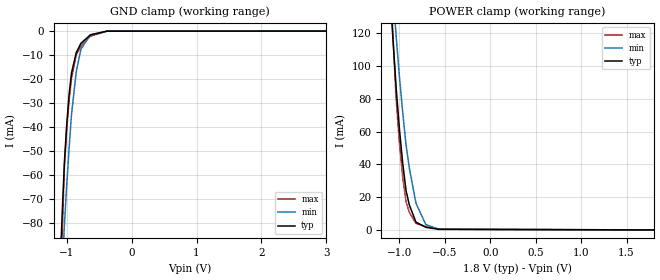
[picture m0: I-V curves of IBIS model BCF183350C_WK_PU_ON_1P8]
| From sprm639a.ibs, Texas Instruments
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|BCF183350C_WK_PD_ON_1P8; WEAK_PULLDOWN_ON
|   Model Cell BCF183350C_WK_PU_ON_1P8
|BCF183350C_WK_PU_ON_1P8
[Model]   BCF183350C_WK_PU_ON_1P8
Model_type   Input
Polarity   Non-Inverting
Vinl =  0.63
Vinh =  1.17
C_comp   1.111906p   0.9691991p   1.265789p
[Model Spec]
Vinl   0.63   0.63   0.63
Vinh   1.17   1.17   1.17
[Temperature Range]   25   155   -40
[Voltage Range]   1.8   1.62   1.98
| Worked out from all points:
|   GND clamp passes 1 mA (typ) near -0.60 V on its own axis
|   POWER clamp passes 1 mA (typ) near -0.65 V on its own axis
| Nom Voltages:
|   VDD=1.2, VDDS=1.8, VSS=0
| Min Voltages:
|   VDD=1.08, VDDS=1.62, VSS=0
| Max Voltages:
|   VDD=1.32, VDDS=1.98, VSS=0
[POWER_clamp]
|   voltage   I(typ)   I(min)   I(max)
-1.8V     884.3mA    853.3mA    1.248A
-1.109V   150.5mA    176mA      165.6mA
-1.073V   117.6mA    146.3mA    120.4mA
-1.036V   86.46mA    118mA      79.88mA
-1V       61.32mA    93.41mA    52.76mA
-963.6mV  40.46mA    71.37mA    31.87mA
-927.3mV  23.9mA     51.85mA    17.21mA
-890.9mV  15.18mA    37.69mA    10.66mA
-818.2mV  4.731mA    16.3mA     3.984mA
-709.1mV  1.569mA    3.203mA    2.036mA
-563.6mV  346uA      430.5uA    445.2uA
1.8V      -22.95uA   -10.4uA    -41.17uA
[GND_clamp]
|   voltage   I(typ)   I(min)   I(max)
-1.8V     -722.8mA   -541.3mA   -1.24A
-1.109V   -103.2mA   -119.1mA   -124.9mA
-1.073V   -77.59mA   -99.55mA   -86.64mA
-1.036V   -54.39mA   -80.71mA   -56.17mA
-1V       -38.52mA   -63.93mA   -40.94mA
-963.6mV  -26.23mA   -48.65mA   -28.77mA
-927.3mV  -17.51mA   -34.87mA   -19.65mA
-854.5mV  -9.047mA   -16.96mA   -9.997mA
-781.8mV  -5.081mA   -7.519mA   -6.26mA
-636.4mV  -1.594mA   -1.566mA   -2.137mA
-381.8mV  -30.33uA   -36.45uA   -47.86uA
3.6V      0A         0A         0A
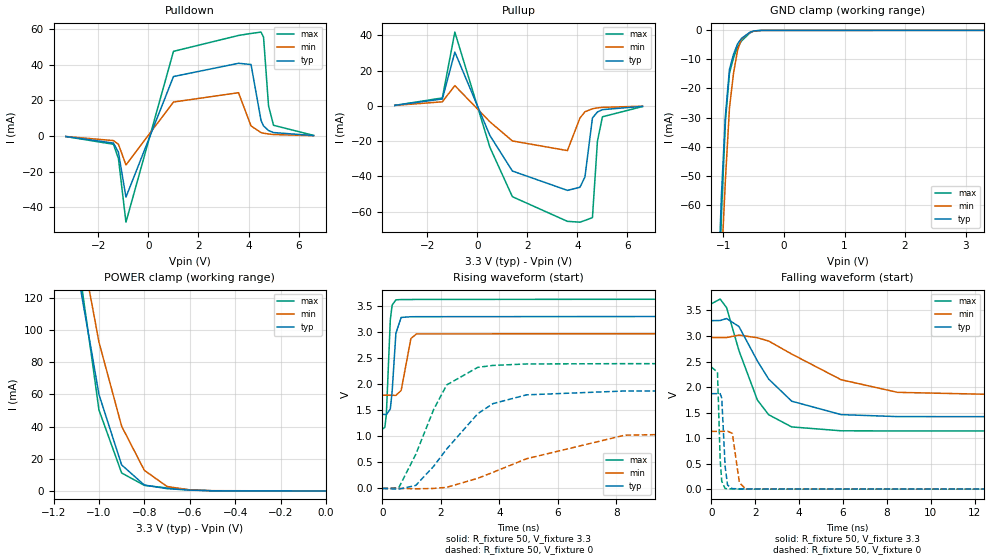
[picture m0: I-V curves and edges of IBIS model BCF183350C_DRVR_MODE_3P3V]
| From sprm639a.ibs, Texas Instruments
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|   Model Cell BCF183350C_DRVR_MODE_3P3V
|BCF183350C_DRVR_MODE_3P3V
[Model]   BCF183350C_DRVR_MODE_3P3V
Model_type   I/O
Polarity   Non-Inverting
Enable   Active-Low
Vinl =  0.8
Vinh =  2
Cref =  15.0000pF
Rref =  100.0000M
Vref =  0V
Vmeas =  1.65
C_comp   1.082155p   0.9471713p   1.221547p
[Model Spec]
Vinl   0.8   0.8   0.8
Vinh   2   2   2
[Temperature Range]   25   155   -40
[Voltage Range]   3.3   2.97   3.63
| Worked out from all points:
|   slope of the pulldown table from 0 to 0.495 V, typ, clamps not added: 24.2 ohm
|   slope of the pullup table from 0 to 0.495 V, typ, clamps not added: 29.8 ohm
|   GND clamp passes 1 mA (typ) near -0.59 V on its own axis
|   POWER clamp passes 1 mA (typ) near -0.65 V on its own axis
|   rising waveform, R_fixture 50, V_fixture 3.3: 20-80 % time 128ps typ, 198ps min, 102ps max; typ from 1.42 V to 3.3 V
|   rising waveform, R_fixture 50, V_fixture 0: 20-80 % time 1.71ns typ, 3.54ns min, 1.11ns max; typ from 0 V to 1.87 V
|   falling waveform, R_fixture 50, V_fixture 3.3: 20-80 % time 1.82ns typ, 3.49ns min, 1.28ns max; typ from 3.3 V to 1.42 V
|   falling waveform, R_fixture 50, V_fixture 0: 20-80 % time 116ps typ, 184ps min, 93.5ps max; typ from 1.87 V to 0 V
| Nom Voltages:
|   VDD=1.2, VDDS=3.3, VSS=0
| Min Voltages:
|   VDD=1.08, VDDS=2.97, VSS=0
| Max Voltages:
|   VDD=1.32, VDDS=3.63, VSS=0
[POWER_clamp]
|   voltage   I(typ)   I(min)   I(max)
-3.3V     2.318A     2.595A     3.049A
-1.1V     141.5mA    168mA      152.3mA
-1.067V   114.3mA    142.9mA    118.3mA
-1.033V   87.17mA    117.8mA    84.37mA
-1V       60.01mA    92.63mA    50.4mA
-900mV    16.17mA    40.25mA    11.16mA
-800mV    3.655mA    12.81mA    3.461mA
-700mV    1.415mA    2.754mA    1.844mA
-600mV    504.3uA    641.1uA    658.2uA
-500mV    86.55uA    148.2uA    94.22uA
0V        39.59pA    2.724nA    9.703pA
[Pulldown]
|   voltage   I(typ)   I(min)   I(max)
-3.3V     -252.1uA   -234.7uA   -277.7uA
-1.4V     -3.919mA   -2.547mA   -4.608mA
-1.2V     -9.103mA   -4.609mA   -12.64mA
-900mV    -34.3mA    -16.21mA   -48.36mA
1V        33.43mA    19.12mA    47.58mA
3.6V      40.87mA    24.35mA    56.5mA
4.1V      40.18mA    5.681mA    57.63mA
4.5V      8.744mA    1.956mA    58.39mA
4.6V      5.703mA    1.616mA    55.56mA
4.8V      3.099mA    1.152mA    16.91mA
5V        1.969mA    859.8uA    6.049mA
6.6V      281.1uA    214.2uA    387.2uA
[Pullup]
|   voltage   I(typ)   I(min)   I(max)
-3.3V     278.9uA    242.8uA    252.3uA
-1.4V     3.885mA    2.29mA     4.485mA
-900mV    30.46mA    11.45mA    41.76mA
500mV     -16.76mA   -9.024mA   -23.45mA
1.4V      -36.9mA    -19.86mA   -51.44mA
3.6V      -47.86mA   -25.33mA   -65.39mA
4.1V      -46.11mA   -6.928mA   -65.87mA
4.3V      -40.29mA   -3.368mA   -64.88mA
4.6V      -6.878mA   -1.656mA   -63.29mA
4.8V      -3.477mA   -1.154mA   -20.01mA
5V        -2.143mA   -846.4uA   -6.19mA
6.6V      -290.9uA   -205.6uA   -395.4uA
[GND_clamp]
|   voltage   I(typ)   I(min)   I(max)
-3.3V     -1.888A    -1.585A    -3.154A
-1.1V     -95.78mA   -113.9mA   -112.1mA
-1.033V   -56.7mA    -80.3mA    -63.61mA
-966.7mV  -29.24mA   -51.23mA   -31.16mA
-900mV    -13.41mA   -26.67mA   -14.73mA
-833.3mV  -8.233mA   -14.78mA   -9.457mA
-766.7mV  -4.676mA   -6.859mA   -5.761mA
-700mV    -2.737mA   -2.908mA   -3.644mA
-566.7mV  -742.7uA   -781uA     -966.3uA
-500mV    -188.9uA   -280.3uA   -215.5uA
-366.7mV  -8.774uA   -27.7uA    -8.181uA
3.3V      39.6pA     4.205uA    5.431pA
[Ramp]
| variable   typ   min   max
dV/dt_f  1.1758617/1.846144n  0.73903365/3.5514619n  1.5506713/1.2961218n
dV/dt_r  1.1445796/1.7390229n 0.69388235/3.5983554n  1.4637814/1.1275634n
R_load = 50
[Rising Waveform]
R_fixture = 50
V_fixture = 3.3
V_fixture_min = 2.97
V_fixture_max = 3.63
|   time   V(typ)   V(min)   V(max)
0s        1.419V     1.788V     1.139V
82.8ps    1.418V     1.788V     1.17V
135.4ps   1.416V     1.788V     1.423V
269.5ps   1.522V     1.788V     3.228V
331.9ps   1.853V     1.787V     3.513V
460.8ps   2.974V     1.783V     3.615V
641.7ps   3.278V     1.879V     3.621V
973.8ps   3.291V     2.874V     3.621V
1.165ns   3.292V     2.962V     3.623V
20.01ns   3.3V       2.97V      3.63V
[Rising Waveform]
R_fixture = 50
V_fixture = 0
V_fixture_min = 0
V_fixture_max = 0
|   time   V(typ)   V(min)   V(max)
0s        0V         0V         0V
559.4ps   -13.78mV   0V         13.79mV
1.138ns   57.09mV    -6.903mV   650.1mV
1.753ns   424.7mV    0V         1.513V
2.2ns     757.2mV    21.76mV    1.985V
3.262ns   1.433V     194.6mV    2.321V
3.783ns   1.626V     309.6mV    2.358V
4.93ns    1.794V     569.5mV    2.386V
8.289ns   1.868V     1.021V     2.392V
20.06ns   1.87V      1.132V     2.392V
[Falling Waveform]
R_fixture = 50
V_fixture = 3.3
V_fixture_min = 2.97
V_fixture_max = 3.63
|   time   V(typ)   V(min)   V(max)
0s        3.3V       2.97V      3.63V
402ps     3.303V     2.97V      3.723V
697.8ps   3.342V     2.97V      3.554V
1.261ns   3.184V     3.018V     2.711V
2.099ns   2.511V     2.965V     1.746V
2.613ns   2.156V     2.901V     1.458V
3.663ns   1.723V     2.646V     1.219V
5.917ns   1.46V      2.143V     1.143V
8.488ns   1.421V     1.896V     1.14V
20.01ns   1.419V     1.788V     1.14V
[Falling Waveform]
R_fixture = 50
V_fixture = 0
V_fixture_min = 0
V_fixture_max = 0
|   time   V(typ)   V(min)   V(max)
0s        1.87V      1.132V     2.392V
281.2ps   1.871V     1.132V     2.29V
404ps     1.87V      1.132V     574.1mV
475.6ps   1.785V     1.132V     154.5mV
629.2ps   444.4mV    1.133V     13.38mV
738.5ps   81.72mV    1.136V     6.36mV
959.5ps   10.14mV    1.091V     6.086mV
1.28ns    6.86mV     128.8mV    2.471mV
1.552ns   5.081mV    7.456mV    0V
20.06ns   0V         0V         0V
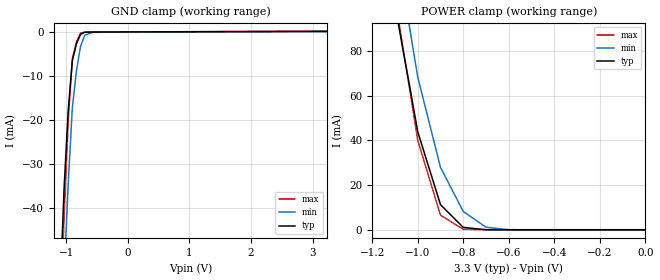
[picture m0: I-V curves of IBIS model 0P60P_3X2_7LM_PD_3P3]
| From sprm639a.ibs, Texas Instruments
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|   Model Cell 0P60P_3X2_7LM_PD_3P3
|IQ0442FS_40P60P_3X2_PD_3P3
[Model]   0P60P_3X2_7LM_PD_3P3
Model_type   Input
Polarity   Non-Inverting
Vinl =  1.55
Vinh =  1.75
C_comp   1.2p   1.2p   1.2p
[Model Spec]
Vinl   1.55   1.42   1.68
Vinh   1.75   1.55   1.85
[Temperature Range]   25   155   -40
[Voltage Range]   3.3   2.97   3.63
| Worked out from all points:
|   GND clamp passes 1 mA (typ) near -0.78 V on its own axis
|   POWER clamp passes 1 mA (typ) near -0.78 V on its own axis
[POWER_clamp]
|   voltage   I(typ)   I(min)   I(max)
-3.3V     1.823A     2.351A     1.96A
-1.1V     100.7mA    129.7mA    104mA
-1.067V   81.79mA    109.2mA    82.71mA
-1.033V   62.86mA    88.78mA    61.4mA
-1V       43.93mA    68.32mA    40.09mA
-900mV    11.35mA    27.98mA    6.644mA
-800mV    1.193mA    8.315mA    343.1uA
-700mV    131.4uA    1.273mA    170.7uA
-600mV    97.55uA    154.6uA    168.7uA
0V        96.5uA     44.2uA     168.6uA
[GND_clamp]
|   voltage   I(typ)   I(min)   I(max)
-3.3V     -1.38A     -1.323A    -2.074A
-1.1V     -59.6mA    -79.12mA   -70.72mA
-1.033V   -35.49mA   -55.25mA   -41.83mA
-966.7mV  -17.83mA   -34.66mA   -20.31mA
-900mV    -6.6mA     -17.33mA   -6.147mA
-833.3mV  -2.744mA   -8.865mA   -2.295mA
-766.7mV  -575.7uA   -3.35mA    -279.2uA
-700mV    -96.31uA   -786.8uA   -98.86uA
-566.7mV  -52.15uA   -88.15uA   -76.87uA
3.233V    96.49uA    44.27uA    168.5uA
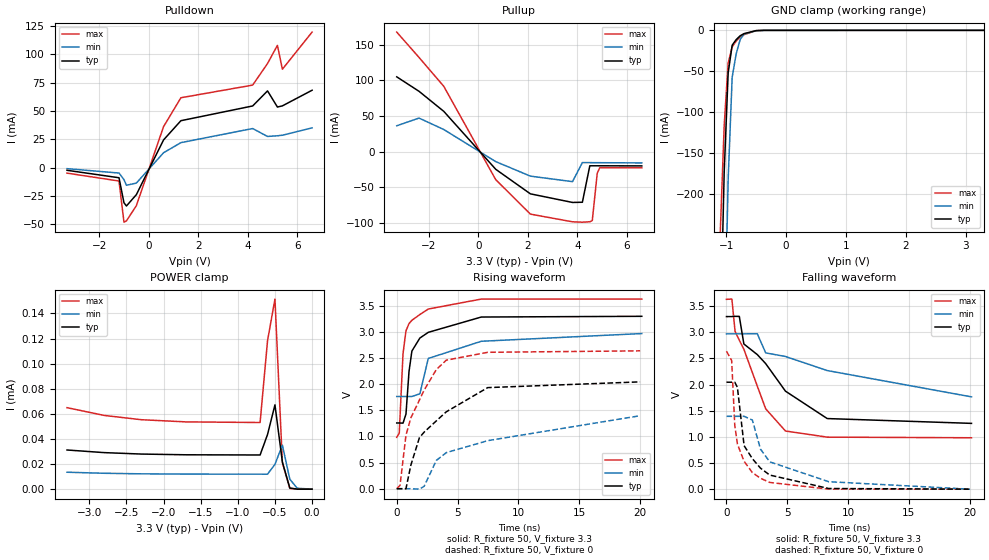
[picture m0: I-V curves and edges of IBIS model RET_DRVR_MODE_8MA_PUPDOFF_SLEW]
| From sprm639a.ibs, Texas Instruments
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|   Model Cell RET_DRVR_MODE_8MA_PUPDOFF_SLEW
|RET_DRVR_MODE_8MA_PUPDOFF_SLEW
[Model]   RET_DRVR_MODE_8MA_PUPDOFF_SLEW
Model_type   I/O
Polarity   Non-Inverting
Enable   Active-Low
Vinl =  0.8
Vinh =  2
Cref =  15.0000pF
Rref =  100.0000M
Vref =  0V
Vmeas =  1.65
C_comp   5.345208p   4.561426p   6.022817p
[Model Spec]
Vinl   0.8   0.8   0.8
Vinh   2   2   2
[Temperature Range]   25   155   -40
[Voltage Range]   3.3   2.97   3.63
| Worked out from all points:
|   slope of the pulldown table from 0 to 0.495 V, typ, clamps not added: 23.8 ohm
|   slope of the pullup table from 0 to 0.495 V, typ, clamps not added: 27.8 ohm
|   GND clamp passes 1 mA (typ) near -0.55 V on its own axis
|   rising waveform, R_fixture 50, V_fixture 3.3: 20-80 % time 1.11ns typ, 2.87ns min, 574ps max; typ from 1.26 V to 3.3 V
|   rising waveform, R_fixture 50, V_fixture 0: 20-80 % time 3.73ns typ, 8.01ns min, 2.27ns max; typ from 0 V to 2.04 V
|   falling waveform, R_fixture 50, V_fixture 3.3: 20-80 % time 4.3ns typ, 8.66ns min, 2.62ns max; typ from 3.3 V to 1.26 V
|   falling waveform, R_fixture 50, V_fixture 0: 20-80 % time 1.66ns typ, 3.52ns min, 947ps max; typ from 2.04 V to 0 V
| Nom Voltages:
|   BIASFET=3.3, VDD=1.2, VDDS=3.3, VSS=0
| Min Voltages:
|   BIASFET=2.97, VDD=1.08, VDDS=2.97, VSS=0
| Max Voltages:
|   BIASFET=3.63, VDD=1.32, VDDS=3.63, VSS=0
[POWER_clamp]
|   voltage   I(typ)   I(min)   I(max)
-3.3V     31.22uA    13.5uA     64.95uA
-2.8V     29.13uA    12.67uA    58.77uA
-2.3V     27.98uA    12.22uA    55.36uA
-1.7V     27.4uA     12.01uA    53.62uA
-700mV    27.24uA    11.95uA    53.12uA
-600mV    43.52uA    11.94uA    118.2uA
-500mV    67.2uA     19.79uA    151.5uA
-400mV    21.58uA    35.09uA    21.1uA
-300mV    927.4nA    7.958uA    611.4nA
-200mV    28.93nA    716.3nA    11.51nA
0V        696.9pA    39.48nA    568.3pA
[Pulldown]
|   voltage   I(typ)   I(min)   I(max)
-3.3V     -2.325mA   -885.1uA   -4.829mA
-1.2V     -8.9mA     -4.742mA   -11.78mA
-1V       -30.94mA   -10.56mA   -48.07mA
-900mV    -33.77mA   -15.53mA   -46.9mA
-500mV    -23.82mA   -13.61mA   -33.55mA
600mV     24.46mA    13.16mA    36.18mA
1.3V      41.39mA    22.04mA    61.62mA
4.2V      54.39mA    34.49mA    72.77mA
4.8V      67.66mA    27.49mA    91.8mA
5.2V      53.41mA    28.11mA    107.8mA
5.4V      54.46mA    28.58mA    86.79mA
6.6V      68.25mA    35.07mA    119.5mA
[Pullup]
|   voltage   I(typ)   I(min)   I(max)
-3.3V     105mA      36.43mA    167.7mA
-2.4V     84.74mA    47.23mA    132.2mA
-1.4V     56.66mA    31.22mA    91.73mA
700mV     -24.56mA   -13.78mA   -39.08mA
2.1V      -58.93mA   -34.12mA   -87.33mA
3.8V      -70.97mA   -41.82mA   -98.09mA
4.2V      -70.71mA   -15.14mA   -98.64mA
4.5V      -19.61mA   -15.2mA    -98.06mA
4.6V      -19.61mA   -15.22mA   -96.39mA
4.8V      -19.61mA   -15.26mA   -30.07mA
4.9V      -19.62mA   -15.28mA   -22.42mA
6.6V      -19.78mA   -15.6mA    -22.44mA
[GND_clamp]
|   voltage   I(typ)   I(min)   I(max)
-3.3V     -16.36A    -15.08A    -17.18A
-1.1V     -382.1mA   -717.8mA   -250.1mA
-1.033V   -173.3mA   -402.2mA   -116.4mA
-966.7mV  -52.02mA   -182.1mA   -39.81mA
-900mV    -18.21mA   -57.43mA   -20.34mA
-833.3mV  -11.36mA   -28.88mA   -13.17mA
-766.7mV  -6.618mA   -11.27mA   -8.134mA
-700mV    -3.983mA   -4.59mA    -5.247mA
-500mV    -328.3uA   -481.4uA   -374.5uA
-366.7mV  -15.94uA   -50.74uA   -14.83uA
3.3V      696.9pA    15.84uA    426.1pA
[Ramp]
| variable   typ   min   max
dV/dt_f  1.2310053/4.2984771n 0.72730904/8.6502749n  1.5950479/2.6227934n
dV/dt_r  1.2344632/3.7306612n 0.84436844/8.0035235n  1.5896397/2.2660664n
R_load = 50
[Rising Waveform]
R_fixture = 50
V_fixture = 3.3
V_fixture_min = 2.97
V_fixture_max = 3.63
|   time   V(typ)   V(min)   V(max)
0s        1.258V     1.765V     983.7mV
206.9ps   1.258V     1.765V     1.064V
516.9ps   1.255V     1.765V     2.584V
759.5ps   1.429V     1.765V     3.022V
1.01ns    2.244V     1.765V     3.161V
1.247ns   2.635V     1.765V     3.224V
1.901ns   2.884V     1.817V     3.334V
2.594ns   2.993V     2.493V     3.439V
6.952ns   3.286V     2.822V     3.63V
20.15ns   3.3V       2.97V      3.63V
[Rising Waveform]
R_fixture = 50
V_fixture = 0
V_fixture_min = 0
V_fixture_max = 0
|   time   V(typ)   V(min)   V(max)
0s        0V         0V         0V
270.4ps   0V         0V         65.09mV
758.6ps   0V         0V         1.024V
1.158ns   448.9mV    0V         1.354V
1.863ns   975.4mV    -8.845mV   1.696V
2.256ns   1.084V     46.58mV    1.888V
3.254ns   1.298V     540.6mV    2.28V
4.073ns   1.472V     690.5mV    2.46V
7.482ns   1.935V     919.8mV    2.611V
20.01ns   2.045V     1.397V     2.639V
[Falling Waveform]
R_fixture = 50
V_fixture = 3.3
V_fixture_min = 2.97
V_fixture_max = 3.63
|   time   V(typ)   V(min)   V(max)
0s        3.3V       2.97V      3.63V
446.6ps   3.3V       2.97V      3.635V
708.9ps   3.305V     2.97V      3.017V
1.059ns   3.303V     2.97V      2.846V
1.432ns   2.776V     2.97V      2.676V
2.538ns   2.573V     2.971V     1.97V
3.225ns   2.401V     2.606V     1.537V
4.853ns   1.874V     2.537V     1.112V
8.287ns   1.35V      2.268V     994.9mV
20.15ns   1.258V     1.765V     982.8mV
[Falling Waveform]
R_fixture = 50
V_fixture = 0
V_fixture_min = 0
V_fixture_max = 0
|   time   V(typ)   V(min)   V(max)
0s        2.045V     1.393V     2.639V
428.9ps   2.045V     1.393V     2.46V
683.5ps   2.046V     1.393V     1.227V
899.9ps   1.948V     1.393V     863.5mV
1.452ns   831.8mV    1.393V     532.3mV
2.131ns   583.4mV    1.322V     317.2mV
2.796ns   402.7mV    766.9mV    208.8mV
3.559ns   269.5mV    522.1mV    128.7mV
8.418ns   12.57mV    142.3mV    0V
20.01ns   0V         0V         0V
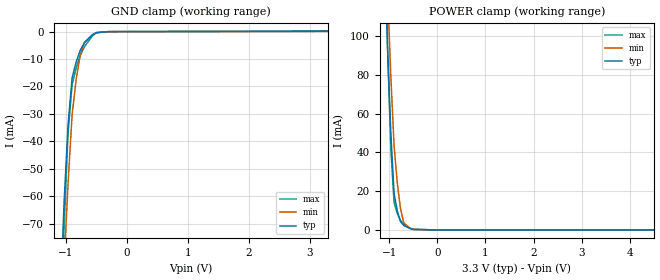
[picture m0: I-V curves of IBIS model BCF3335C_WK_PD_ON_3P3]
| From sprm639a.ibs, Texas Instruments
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|   Model Cell BCF3335C_WK_PD_ON_3P3
|BCF3335C_WK_PD_ON_3P3
[Model]   BCF3335C_WK_PD_ON_3P3
Model_type   Input
Polarity   Non-Inverting
Vinl =  0.8
Vinh =  2
C_comp   1.21278p   1.078036p   1.350148p
[Model Spec]
Vinl   0.8   0.8   0.8
Vinh   2   2   2
[Temperature Range]   25   155   -40
[Voltage Range]   3.3   2.97   3.63
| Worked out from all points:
|   GND clamp passes 1 mA (typ) near -0.55 V on its own axis
|   POWER clamp passes 1 mA (typ) near -0.59 V on its own axis
| Nom Voltages:
|   VDD=1.2, VDDS=3.3, VSS=0
| Min Voltages:
|   VDD=1.08, VDDS=2.97, VSS=0
| Max Voltages:
|   VDD=1.32, VDDS=3.63, VSS=0
[POWER_clamp]
|   voltage   I(typ)   I(min)   I(max)
-3.3V     2.319A     2.596A     3.052A
-1.1V     147.6mA    172.2mA    162.6mA
-1.033V   92.44mA    121.8mA    91.38mA
-966.7mV  49.54mA    78.89mA    41.94mA
-900mV    18.9mA     43.53mA    14.24mA
-833.3mV  9.848mA    24.4mA     8.546mA
-766.7mV  4.338mA    11.11mA    4.856mA
-700mV    2.371mA    3.663mA    3.173mA
-566.7mV  699.6uA    771.9uA    944.8uA
-500mV    248.7uA    286.4uA    332.8uA
33.33mV   0A         0A         0A
6.6V      0A         0A         0A
[GND_clamp]
|   voltage   I(typ)   I(min)   I(max)
-3.3V     -1.89A     -1.587A    -3.158A
-1.1V     -103.3mA   -119.1mA   -124.2mA
-1.033V   -62.96mA   -85.24mA   -71.87mA
-966.7mV  -34.19mA   -55.64mA   -36.89mA
-900mV    -16.94mA   -30.34mA   -19.31mA
-833.3mV  -11.09mA   -17.42mA   -13.31mA
-766.7mV  -6.833mA   -8.649mA   -8.755mA
-700mV    -4.167mA   -4.016mA   -5.634mA
-566.7mV  -1.181mA   -1.18mA    -1.555mA
-500mV    -336.1uA   -449.6uA   -399.2uA
-300mV    -27.98uA   -20.4uA    -40.75uA
3.3V      107.2uA    58.03uA    177.9uA
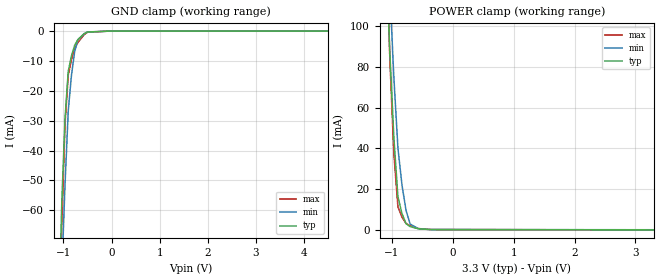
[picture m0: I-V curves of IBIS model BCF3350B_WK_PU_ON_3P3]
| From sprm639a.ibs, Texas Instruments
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|BCF3350B_WK_PD_ON_3P3; WEAK_PULLDOWN_ON
|   Model Cell BCF3350B_WK_PU_ON_3P3
|BCF3350B_WK_PU_ON_3P3
[Model]   BCF3350B_WK_PU_ON_3P3
Model_type   Input
Polarity   Non-Inverting
Vinl =  0.8
Vinh =  2
C_comp   1.081689p   0.9467568p   1.2214p
[Model Spec]
Vinl   0.8   0.8   0.8
Vinh   2   2   2
[Temperature Range]   25   155   -40
[Voltage Range]   3.3   2.97   3.63
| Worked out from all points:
|   GND clamp passes 1 mA (typ) near -0.58 V on its own axis
|   POWER clamp passes 1 mA (typ) near -0.65 V on its own axis
| Nom Voltages:
|   VDD=1.2, VDDS=3.3, VSS=0
| Min Voltages:
|   VDD=1.08, VDDS=2.97, VSS=0
| Max Voltages:
|   VDD=1.32, VDDS=3.63, VSS=0
[POWER_clamp]
|   voltage   I(typ)   I(min)   I(max)
-3.3V     2.318A     2.595A     3.049A
-1.1V     141.5mA    168mA      152.4mA
-1.033V   87.22mA    117.8mA    84.46mA
-966.7mV  45.45mA    75.19mA    37.43mA
-900mV    16.24mA    40.27mA    11.28mA
-833.3mV  7.9mA      21.98mA    6.136mA
-766.7mV  2.98mA     9.488mA    3.023mA
-700mV    1.481mA    2.786mA    1.936mA
-566.7mV  418.3uA    505.1uA    545.1uA
-366.7mV  37.54uA    32.82uA    50.64uA
3.3V      -108.8uA   -58.67uA   -174uA
[GND_clamp]
|   voltage   I(typ)   I(min)   I(max)
-3.3V     -1.888A    -1.585A    -3.154A
-1.1V     -95.8mA    -113.9mA   -112.1mA
-1.033V   -56.72mA   -80.31mA   -63.63mA
-966.7mV  -29.27mA   -51.24mA   -31.19mA
-900mV    -13.44mA   -26.69mA   -14.78mA
-833.3mV  -8.296mA   -14.8mA    -9.57mA
-766.7mV  -4.761mA   -6.885mA   -5.913mA
-700mV    -2.841mA   -2.943mA   -3.814mA
-566.7mV  -850.9uA   -829.9uA   -1.14mA
-500mV    -297.8uA   -331.1uA   -390.3uA
-33.33mV  0A         0A         0A
6.6V      0A         0A         0A
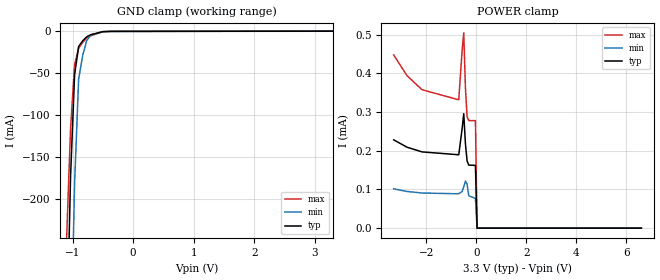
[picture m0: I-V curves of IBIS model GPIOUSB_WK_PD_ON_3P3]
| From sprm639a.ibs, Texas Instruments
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|USB_8MA_OPEN_DRAIN; 8MA_OPEN_DRAIN
|   Model Cell GPIOUSB_WK_PD_ON_3P3
|GPIOUSB_WK_PD_ON_3P3
[Model]   GPIOUSB_WK_PD_ON_3P3
Model_type   Input
Polarity   Non-Inverting
Vinl =  0.8
Vinh =  2
C_comp   5.34973p   4.565931p   6.027791p
[Model Spec]
Vinl   0.8   0.8   0.8
Vinh   2   2   2
[Temperature Range]   25   155   -40
[Voltage Range]   3.3   2.97   3.63
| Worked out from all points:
|   GND clamp passes 1 mA (typ) near -0.55 V on its own axis
| Nom Voltages:
|   BIASFET=3.3, VDD=1.2, VDDS=3.3, VSS=0
| Min Voltages:
|   BIASFET=2.97, VDD=1.08, VDDS=2.97, VSS=0
| Max Voltages:
|   BIASFET=3.63, VDD=1.32, VDDS=3.63, VSS=0
[POWER_clamp]
|   voltage   I(typ)   I(min)   I(max)
-3.3V     228.1uA    101.6uA    447.3uA
-2.767V   209.1uA    94.76uA    393.9uA
-2.167V   197uA      90.77uA    357.6uA
-700mV    189.6uA    88.78uA    331.6uA
-566.7mV  256.1uA    94.78uA    457.7uA
-500mV    295.8uA    106.8uA    504.4uA
-433.3mV  218.2uA    121.6uA    363.3uA
-366.7mV  173.9uA    113.9uA    287.8uA
-300mV    162.9uA    83.62uA    278.1uA
-33.33mV  162.2uA    76.8uA     277.6uA
33.33mV   0A         0A         0A
6.6V      0A         0A         0A
[GND_clamp]
|   voltage   I(typ)   I(min)   I(max)
-3.3V     -16.36A    -15.08A    -17.18A
-1.1V     -382.1mA   -717.8mA   -250.1mA
-1.033V   -173.3mA   -402.2mA   -116.4mA
-966.7mV  -52.02mA   -182.1mA   -39.8mA
-900mV    -18.2mA    -57.43mA   -20.33mA
-833.3mV  -11.36mA   -28.89mA   -13.17mA
-766.7mV  -6.626mA   -11.28mA   -8.158mA
-700mV    -4.013mA   -4.598mA   -5.306mA
-500mV    -405.1uA   -515.9uA   -494.1uA
-366.7mV  -78.5uA    -83.36uA   -110.5uA
3.3V      162.1uA    90.6uA     277.3uA
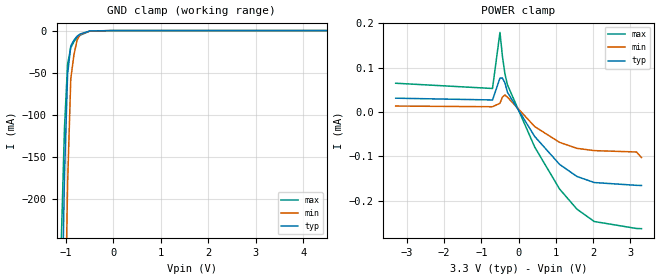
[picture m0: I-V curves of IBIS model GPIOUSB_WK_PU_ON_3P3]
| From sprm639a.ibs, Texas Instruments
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|   Model Cell GPIOUSB_WK_PU_ON_3P3
|GPIOUSB_WK_PU_ON_3P3
[Model]   GPIOUSB_WK_PU_ON_3P3
Model_type   Input
Polarity   Non-Inverting
Vinl =  0.8
Vinh =  2
C_comp   5.34973p   4.565931p   6.027791p
[Model Spec]
Vinl   0.8   0.8   0.8
Vinh   2   2   2
[Temperature Range]   25   155   -40
[Voltage Range]   3.3   2.97   3.63
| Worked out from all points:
|   GND clamp passes 1 mA (typ) near -0.54 V on its own axis
| Nom Voltages:
|   BIASFET=3.3, VDD=1.2, VDDS=3.3, VSS=0
| Min Voltages:
|   BIASFET=2.97, VDD=1.08, VDDS=2.97, VSS=0
| Max Voltages:
|   BIASFET=3.63, VDD=1.32, VDDS=3.63, VSS=0
[POWER_clamp]
|   voltage   I(typ)   I(min)   I(max)
-3.3V     31.22uA    13.5uA     64.95uA
-700mV    27.24uA    11.95uA    53.12uA
-500mV    76.48uA    19.77uA    179.6uA
-433.3mV  76.57uA    33.82uA    125.7uA
-366.7mV  66uA       38.46uA    86.4uA
-300mV    44.74uA    33.7uA     61.57uA
433.3mV   -55.14uA   -32.83uA   -78.95uA
1.1V      -118uA     -68.32uA   -173.5uA
1.567V    -145.3uA   -81.87uA   -219uA
2.033V    -159uA     -87.03uA   -246.9uA
3.167V    -165.3uA   -90.11uA   -262.6uA
3.3V      -165.6uA   -102.8uA   -263uA
[GND_clamp]
|   voltage   I(typ)   I(min)   I(max)
-3.3V     -16.36A    -15.08A    -17.18A
-1.1V     -382.1mA   -717.8mA   -250.1mA
-1.033V   -173.3mA   -402.2mA   -116.4mA
-966.7mV  -52.02mA   -182.1mA   -39.81mA
-900mV    -18.21mA   -57.44mA   -20.35mA
-833.3mV  -11.38mA   -28.89mA   -13.21mA
-766.7mV  -6.658mA   -11.29mA   -8.223mA
-700mV    -4.058mA   -4.616mA   -5.385mA
-500mV    -482.9uA   -556.9uA   -624.5uA
-33.33mV  0A         0A         0A
6.6V      0A         0A         0A
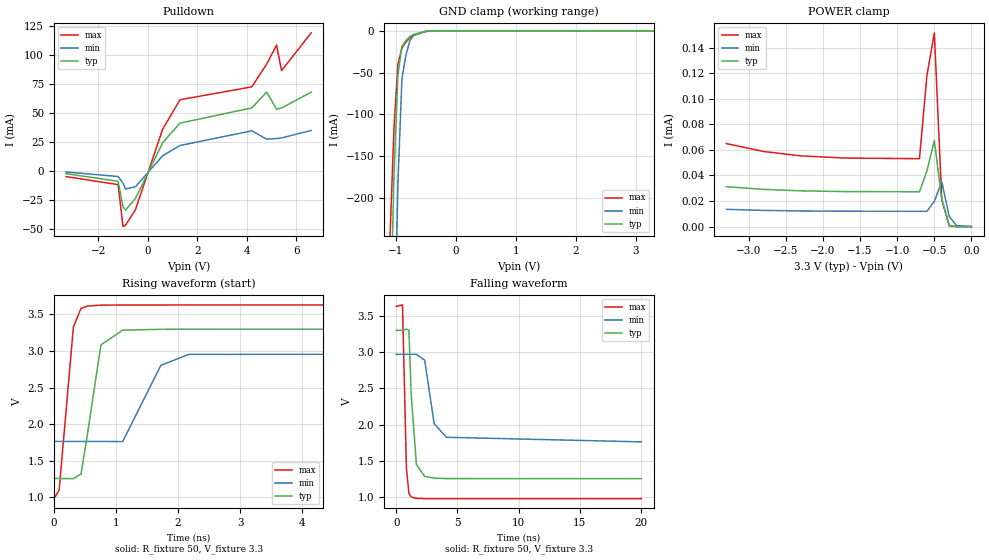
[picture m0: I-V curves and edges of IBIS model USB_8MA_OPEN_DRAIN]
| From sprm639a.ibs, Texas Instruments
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|   Model Cell USB_8MA_OPEN_DRAIN
|USB_8MA_OPEN_DRAIN
[Model]   USB_8MA_OPEN_DRAIN
Model_type   I/O_open_drain
Polarity   Inverting
Enable   Active-Low
Vinl =  0.8
Vinh =  2
Cref =  15.0000pF
Rref =  100.0000M
Vref =  0V
Vmeas =  1.65
C_comp   5.34973p   4.565931p   6.027791p
[Model Spec]
Vinl   0.8   0.8   0.8
Vinh   2   2   2
[Temperature Range]   25   155   -40
[Voltage Range]   3.3   2.97   3.63
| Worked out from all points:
|   slope of the pulldown table from 0 to 0.495 V, typ, clamps not added: 23.8 ohm
|   GND clamp passes 1 mA (typ) near -0.55 V on its own axis
|   rising waveform, R_fixture 50, V_fixture 3.3: 20-80 % time 202ps typ, 323ps min, 146ps max; typ from 1.26 V to 3.3 V
|   falling waveform, R_fixture 50, V_fixture 3.3: 20-80 % time 369ps typ, 720ps min, 222ps max; typ from 3.3 V to 1.26 V
| Nom Voltages:
|   BIASFET=3.3, VDD=1.2, VDDS=3.3, VSS=0
| Min Voltages:
|   BIASFET=2.97, VDD=1.08, VDDS=2.97, VSS=0
| Max Voltages:
|   BIASFET=3.63, VDD=1.32, VDDS=3.63, VSS=0
[POWER_clamp]
|   voltage   I(typ)   I(min)   I(max)
-3.3V     31.22uA    13.5uA     64.95uA
-2.8V     29.13uA    12.67uA    58.77uA
-2.3V     27.98uA    12.22uA    55.36uA
-1.7V     27.4uA     12.01uA    53.62uA
-700mV    27.24uA    11.95uA    53.12uA
-600mV    43.52uA    11.94uA    118.2uA
-500mV    67.21uA    19.79uA    151.6uA
-400mV    21.58uA    35.11uA    21.1uA
-300mV    927.4nA    7.959uA    611.4nA
-200mV    28.93nA    716.3nA    11.51nA
0V        696.9pA    39.48nA    568.3pA
[Pulldown]
|   voltage   I(typ)   I(min)   I(max)
-3.3V     -2.325mA   -885.1uA   -4.829mA
-1.2V     -8.9mA     -4.742mA   -11.78mA
-1V       -30.94mA   -10.56mA   -48.07mA
-900mV    -33.77mA   -15.53mA   -46.9mA
-500mV    -23.82mA   -13.61mA   -33.55mA
600mV     24.46mA    13.16mA    36.18mA
1.3V      41.39mA    22.04mA    61.62mA
4.2V      54.57mA    34.77mA    72.77mA
4.8V      68.22mA    27.49mA    92.41mA
5.2V      53.41mA    28.11mA    108.9mA
5.4V      54.46mA    28.58mA    86.79mA
6.6V      68.25mA    35.07mA    119.5mA
[GND_clamp]
|   voltage   I(typ)   I(min)   I(max)
-3.3V     -16.36A    -15.08A    -17.18A
-1.1V     -382.1mA   -717.8mA   -250.1mA
-1.033V   -173.3mA   -402.2mA   -116.4mA
-966.7mV  -52.02mA   -182.1mA   -39.81mA
-900mV    -18.21mA   -57.43mA   -20.34mA
-833.3mV  -11.36mA   -28.88mA   -13.17mA
-766.7mV  -6.618mA   -11.27mA   -8.134mA
-700mV    -3.983mA   -4.59mA    -5.247mA
-500mV    -328.3uA   -481.4uA   -374.5uA
-366.7mV  -15.94uA   -50.74uA   -14.83uA
3.3V      696.9pA    15.85uA    426.1pA
[Ramp]
| variable   typ   min   max
dV/dt_f  1.2435216/0.37043762n 0.73534822/0.72019621n  1.6127085/0.22297403n
dV/dt_r  1.2644443/0.33444283n 0.86590685/0.74181111n  1.6251292/0.20296461n
R_load = 50
[Rising Waveform]
R_fixture = 50
V_fixture = 3.3
V_fixture_min = 2.97
V_fixture_max = 3.63
|   time   V(typ)   V(min)   V(max)
0s        1.258V     1.765V     982.5mV
85.2ps    1.258V     1.765V     1.096V
315.7ps   1.257V     1.765V     3.333V
437.8ps   1.319V     1.765V     3.583V
542.5ps   1.871V     1.765V     3.615V
758.1ps   3.083V     1.765V     3.627V
1.108ns   3.285V     1.763V     3.629V
1.723ns   3.297V     2.804V     3.629V
2.171ns   3.298V     2.954V     3.63V
20.04ns   3.3V       2.97V      3.63V
[Falling Waveform]
R_fixture = 50
V_fixture = 3.3
V_fixture_min = 2.97
V_fixture_max = 3.63
|   time   V(typ)   V(min)   V(max)
0s        3.3V       2.97V      3.63V
514.8ps   3.3V       2.97V      3.65V
832.2ps   3.317V     2.97V      1.409V
1.039ns   3.301V     2.97V      1.055V
1.229ns   2.405V     2.97V      1.007V
1.652ns   1.454V     2.97V      988.1mV
2.329ns   1.288V     2.889V     983.7mV
3.102ns   1.266V     2.015V     982.8mV
4.108ns   1.26V      1.828V     982.7mV
20.04ns   1.258V     1.765V     982.8mV
